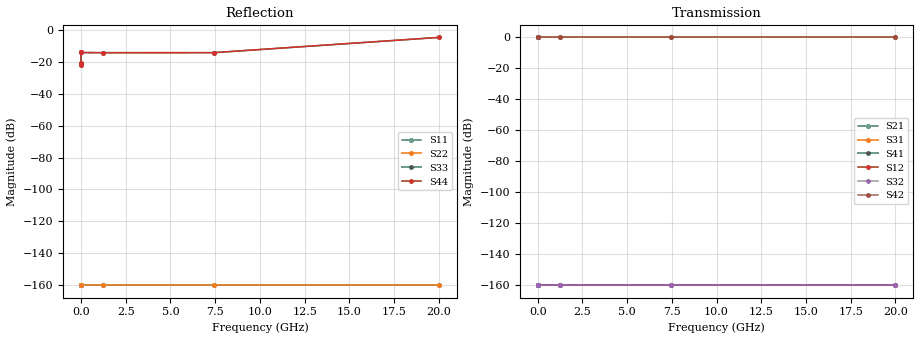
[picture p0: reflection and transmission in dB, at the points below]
! Generated on 04-22-2014 16:27:30
!  1 ----xxxxxxxxxxxxxxxxxx---- 3
!  xxxxxxxxxxxxxxxxxx
!  (Input) xxxxxxxxxxxxxxxxxx  (Output)
!  xxxxxxxxxxxxxxxxxx
!  2 ----xxxxxxxxxxxxxxxxxx---- 4
! FREQ  S11  S12  S13  S14
!  S21  S22  S23  S24
!  S31  S32  S33  S34
!  S41  S42  S43  S44
!  DB  ANG  DB  ANG  DB  ANG  DB  ANG
# HZ S DB R 50.00
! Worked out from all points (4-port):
!   51 points, 1 kHz to 20 GHz, reference 50 ohm
!   strongest paths, dB at 1 kHz, 10.77 kHz, 141.4 kHz, 1.857 GHz, 20 GHz:
!     S42: 0.0, 0.0, 0.0, 0.0, 0.0
!     S31: 0.0, 0.0, 0.0, 0.0, 0.0
!     S43: -19.9, -20.2, -25.3, -27.4, -17.4
!     S41: -, -, -, -, -
!     S32: -, -, -, -, -
!     S21: -, -, -, -, -
!   lowest |S11| = - dB at 1 kHz (marker M1), VSWR 1.00, Z = 50 + j0 ohm
!   |S11| at or under -10 dB: start of sweep to end of sweep
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1000  -300.00 0.0  -300.00 0.0  -300.00 0.0  -300.00 0.0
      -300.00 0.0  -300.00 0.0  -300.00 0.0  -300.00 0.0
      0.00 0.0  -300.00 -3.2  -22.01 -176.9  -19.90 -3.2
      -300.00 -3.2  0.00 0.0  -19.90 -3.2  -22.01 -176.9
7248  -300.00 0.0  -300.00 0.0  -300.00 0.0  -300.00 0.0
      -300.00 0.0  -300.00 0.0  -300.00 0.0  -300.00 0.0
      0.00 0.0  -300.00 -22.7  -20.89 -160.5  -20.05 -22.7
      -300.00 -22.7  0.00 0.0  -20.05 -22.7  -20.89 -160.5
78060  -300.00 0.0  -300.00 0.0  -300.00 0.0  -300.00 0.0
       -300.00 0.0  -300.00 0.0  -300.00 0.0  -300.00 0.0
       0.00 0.0  -300.00 -133.5  -13.77 -168.7  -24.21 -133.5
       -300.00 -133.5  0.00 0.0  -24.21 -133.5  -13.77 -168.7
840800  -300.00 0.0  -300.00 0.0  -300.00 0.0  -300.00 0.0
        -300.00 0.0  -300.00 0.0  -300.00 0.0  -300.00 0.0
        0.00 0.0  -300.00 -177.4  -14.06 -178.4  -27.49 -177.4
        -300.00 -177.4  0.00 0.0  -27.49 -177.4  -14.06 -178.4
1.25e9  -300.00 0.0  -300.00 0.0  -300.00 0.0  -300.00 0.0
        -300.00 0.0  -300.00 0.0  -300.00 0.0  -300.00 0.0
        0.00 0.0  -300.00 -173.8  -14.18 -176.9  -27.71 -173.8
        -300.00 -173.8  0.00 0.0  -27.71 -173.8  -14.18 -176.9
7.429e9  -300.00 0.0  -300.00 0.0  -300.00 0.0  -300.00 0.0
         -300.00 0.0  -300.00 0.0  -300.00 0.0  -300.00 0.0
         0.00 0.0  -300.00 -168.5  -14.16 -141.6  -21.51 -168.5
         -300.00 -168.4  0.00 0.0  -21.47 -168.4  -14.16 -141.5
2e10  -300.00 0.0  -300.00 0.0  -300.00 0.0  -300.00 0.0
      -300.00 0.0  -300.00 0.0  -300.00 0.0  -300.00 0.0
      0.00 0.0  -300.00 111.9  -4.61 -124.8  -17.43 111.9
      -300.00 111.4  0.00 0.0  -17.36 111.4  -4.58 -124.8
